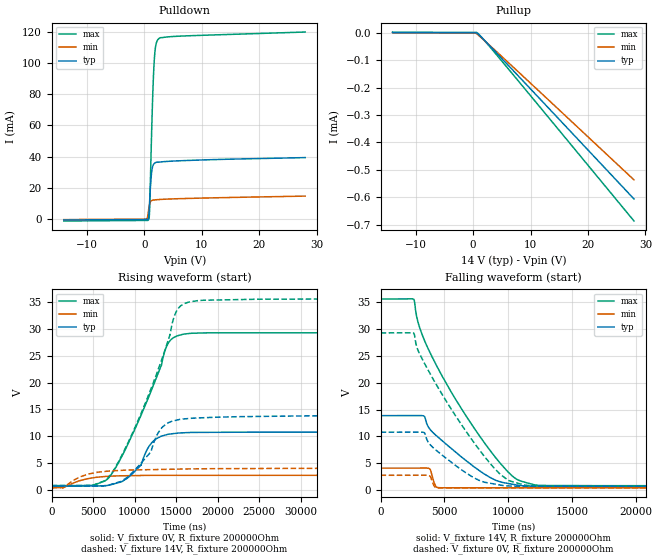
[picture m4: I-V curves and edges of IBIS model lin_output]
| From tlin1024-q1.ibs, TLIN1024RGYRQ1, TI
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|   lin_output Model
[Model]   lin_output
Model_type   Output
Polarity   Non-Inverting
Vmeas = 7
Vref = 0
Cref = 2pF
Rref = 100000
|   typ   min   max
C_comp   3.52891E-11   3.03138E-11   3.67824E-11
| Where Nom  PVT is Nominal Process, 14V, 27C
|   Fast PVT is Strong Process,  36V, -55C
|   Slow PVT is Weak Process,   4V, 165C
[Voltage Range]   14   4   36
|Junction Temperature
[Temperature Range]   27   165   -55
[Pullup Reference]   14   4   36
[Pulldown Reference]   0   -0   0
[Power Clamp Reference]   14   4   36
[GND Clamp Reference]   0   0   0
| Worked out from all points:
|   slope of the pulldown table from 0 to 2.1 V, typ, clamps not added: 57.3 ohm
|   slope of the pullup table from 0 to 2.1 V, typ, clamps not added: 70.3 kohm
|   falling waveform, V_fixture 14V, R_fixture 200000Ohm: 20-80 % time 4.01us typ, 271ns min, 5.15us max; typ from 13.9 V to 0.714 V
|   rising waveform, V_fixture 0V, R_fixture 200000Ohm: 20-80 % time 2.53us typ, 3.05us min, 4.74us max; typ from 0.706 V to 10.8 V
|   rising waveform, V_fixture 14V, R_fixture 200000Ohm: 20-80 % time 3.31us typ, 3.74us min, 5.32us max; typ from 0.714 V to 13.9 V
|   falling waveform, V_fixture 0V, R_fixture 200000Ohm: 20-80 % time 3.24us typ, 224ns min, 4.61us max; typ from 10.8 V to 0.706 V
[Pulldown]
|   Voltage   I(typ)   I(min)   I(max)
-14V      -606uA     -340uA     -1.246mA
364mV     -283.7uA   -40.24uA   -879.2uA
742mV     451.5uA    5.383mA    -514.3uA
868mV     6.335mA    8.362mA    1.192mA
952mV     12.21mA    9.778mA    7.663mA
1.204V    26.9mA     11.63mA    43.93mA
1.414V    32.93mA    12.03mA    71.76mA
1.582V    34.78mA    12.17mA    89.53mA
1.708V    35.45mA    12.23mA    99.38mA
2.002V    36.2mA     12.35mA    111.1mA
2.59V     36.49mA    12.52mA    115.8mA
28V       39.38mA    14.71mA    119.8mA
[Pullup]
|   Voltage   I(typ)   I(min)   I(max)
-14V      1.413uA    828.1nA    2.973uA
280mV     80.71nA    -512.6nA   1.546uA
742mV     -1.698uA   -5.465uA   -286.4nA
2.254V    -33.13uA   -33.45uA   -34.69uA
5.32V     -100.7uA   -92.63uA   -111uA
28V       -606.3uA   -536.7uA   -686.8uA
[Ramp]
R_load = 200000
|   typ   min   max
dV/dt_r   6.04163/2.53141e-06   1.40452/3.00862e-06   17.0758/4.73625e-06
dV/dt_f   7.88762/4.00807e-06   2.19954/2.71273e-07   20.8554/5.14492e-06
[Falling Waveform]
V_fixture = 14V
V_fixture_min = 4V
V_fixture_max = 36V
R_fixture = 200000Ohm
C_fixture = 0F
|   Time   V(typ)   V(min)   V(max)
0s        13.86V     4.089V     35.58V
2.595us   13.87V     4.096V     35.54V
2.975us   13.88V     4.097V     30.93V
3.419us   13.75V     4.098V     27.98V
3.697us   11.96V     4.078V     26.47V
4.463us   9.942V     455.1mV    22.83V
7.357us   4.278V     426mV      11.44V
10.31us   1.095V     426mV      2.641V
12.53us   741.1mV    425.9mV    858.6mV
250us     713.9mV    422.8mV    818mV
[Rising Waveform]
V_fixture = 0V
V_fixture_min = 0V
V_fixture_max = 0V
R_fixture = 200000Ohm
C_fixture = 0F
|   Time   V(typ)   V(min)   V(max)
0s        705.7mV    415.5mV    802.9mV
5.017us   747.8mV    2.271V     866.6mV
6.861us   877.5mV    2.546V     2.253V
10.07us   3.568V     2.678V     11.5V
10.76us   4.611V     2.695V     13.93V
12.03us   8.757V     2.727V     18.67V
14.01us   10.36V     2.729V     27.26V
14.99us   10.55V     2.729V     28.61V
16.66us   10.7V      2.729V     29.15V
250us     10.78V     2.756V     29.26V
[Rising Waveform]
V_fixture = 14V
V_fixture_min = 4V
V_fixture_max = 36V
R_fixture = 200000Ohm
C_fixture = 0F
|   Time   V(typ)   V(min)   V(max)
0s        713.9mV    422.8mV    818mV
5.017us   759.6mV    3.144V     896.3mV
6.958us   956.6mV    3.532V     2.544V
9.038us   2.291V     3.699V     8.311V
11.36us   6.058V     3.768V     16.49V
13.12us   11.32V     3.82V      23.71V
14.99us   12.98V     3.876V     33.16V
15.87us   13.22V     3.902V     34.62V
17.59us   13.4V      3.937V     35.24V
250us     13.86V     4.089V     35.58V
[Falling Waveform]
|Gnd
V_fixture = 0V
V_fixture_min = 0V
V_fixture_max = 0V
R_fixture = 200000Ohm
C_fixture = 0F
|   Time   V(typ)   V(min)   V(max)
0s        10.78V     2.756V     29.26V
2.595us   10.79V     2.763V     29.22V
2.861us   10.79V     2.763V     26.5V
3.419us   10.69V     2.765V     23.7V
4.023us   8.117V     1.775V     21.07V
4.34us    7.449V     455mV      19.76V
7.821us   1.712V     417.9mV    7.23V
9.947us   771.4mV    417.9mV    1.9V
11.66us   724.8mV    417.9mV    847.5mV
250us     705.7mV    415.5mV    802.9mV
